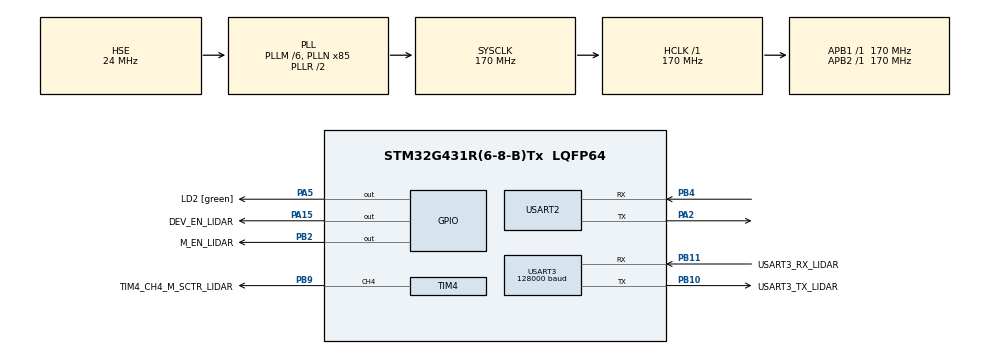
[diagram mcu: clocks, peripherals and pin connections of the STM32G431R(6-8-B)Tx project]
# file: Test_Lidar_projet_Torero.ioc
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Dma.Request0=USART3_TX
Dma.USART3_TX.0.Direction=DMA_MEMORY_TO_PERIPH
Dma.USART3_TX.0.EventEnable=DISABLE
Dma.USART3_TX.0.Instance=DMA1_Channel1
Dma.USART3_TX.0.MemDataAlignment=DMA_MDATAALIGN_BYTE
Dma.USART3_TX.0.MemInc=DMA_MINC_ENABLE
Dma.USART3_TX.0.Mode=DMA_CIRCULAR
Dma.USART3_TX.0.PeriphDataAlignment=DMA_PDATAALIGN_BYTE
Dma.USART3_TX.0.PeriphInc=DMA_PINC_DISABLE
Dma.USART3_TX.0.Polarity=HAL_DMAMUX_REQ_GEN_RISING
Dma.USART3_TX.0.Priority=DMA_PRIORITY_LOW
Dma.USART3_TX.0.RequestNumber=1
Dma.USART3_TX.0.SignalID=NONE
Dma.USART3_TX.0.SyncEnable=DISABLE
Dma.USART3_TX.0.SyncPolarity=HAL_DMAMUX_SYNC_NO_EVENT
Dma.USART3_TX.0.SyncRequestNumber=1
Dma.USART3_TX.0.SyncSignalID=NONE
Mcu.Family=STM32G4
Mcu.Name=STM32G431R(6-8-B)Tx
Mcu.Package=LQFP64
NVIC.DMA1_Channel1_IRQn=true\:0\:0\:false\:false\:true\:false\:true\:true
NVIC.PriorityGroup=NVIC_PRIORITYGROUP_4
PA13.GPIO_Label=T_SWDIO
PA13.Mode=Serial_Wire
PA13.Signal=SYS_JTMS-SWDIO
PA14.GPIO_Label=T_SWCLK
PA14.Mode=Serial_Wire
PA14.Signal=SYS_JTCK-SWCLK
PA15.GPIO_Label=DEV_EN_LIDAR
PA15.Signal=GPIO_Output
PA2.Mode=Asynchronous
PA2.Signal=USART2_TX
PA5.GPIO_Label=LD2 [green]
PA5.Signal=GPIO_Output
PB10.GPIO_Label=USART3_TX_LIDAR
PB10.Mode=Asynchronous
PB10.Signal=USART3_TX
PB11.GPIO_Label=USART3_RX_LIDAR
PB11.Mode=Asynchronous
PB11.Signal=USART3_RX
PB2.GPIO_Label=M_EN_LIDAR
PB2.PinState=GPIO_PIN_SET
PB2.Signal=GPIO_Output
PB3.GPIO_Label=T_SWO
PB3.Signal=SYS_JTDO-SWO
PB4.Mode=Asynchronous
PB4.Signal=USART2_RX
PB9.GPIO_Label=TIM4_CH4_M_SCTR_LIDAR
PB9.Signal=S_TIM4_CH4
PC14-OSC32_IN.GPIO_Label=RCC_OSC32_OUT
PC14-OSC32_IN.Signal=RCC_OSC32_IN
PC15-OSC32_OUT.GPIO_Label=RCC_OSC32_OUT
PC15-OSC32_OUT.Signal=RCC_OSC32_OUT
PF0-OSC_IN.GPIO_Label=RCC_OSC_IN
PF0-OSC_IN.Mode=HSE-External-Oscillator
PF0-OSC_IN.Signal=RCC_OSC_IN
PF1-OSC_OUT.GPIO_Label=RCC_OSC_OUT
PF1-OSC_OUT.Mode=HSE-External-Oscillator
PF1-OSC_OUT.Signal=RCC_OSC_OUT
ProjectManager.HeapSize=0x200
ProjectManager.StackSize=0x400
ProjectManager.TargetToolchain=STM32CubeIDE
RCC.ADC12Freq_Value=170000000
RCC.AHBFreq_Value=170000000
RCC.APB1Freq_Value=170000000
RCC.APB1TimFreq_Value=170000000
RCC.APB2Freq_Value=170000000
RCC.APB2TimFreq_Value=170000000
RCC.CortexFreq_Value=170000000
RCC.EXTERNAL_CLOCK_VALUE=12288000
RCC.HCLKFreq_Value=170000000
RCC.HSE_VALUE=24000000
RCC.HSI48_VALUE=48000000
RCC.HSI_VALUE=16000000
RCC.LSE_VALUE=32768
RCC.PLLM=RCC_PLLM_DIV6
RCC.PLLN=85
RCC.PLLSourceVirtual=RCC_PLLSOURCE_HSE
RCC.RTCClockSelection=RCC_RTCCLKSOURCE_LSE
RCC.SYSCLKFreq_VALUE=170000000
RCC.SYSCLKSource=RCC_SYSCLKSOURCE_PLLCLK
RCC.USBFreq_Value=170000000
RCC.VCOOutputFreq_Value=340000000
SH.S_TIM4_CH4.0=TIM4_CH4,PWM Generation4 CH4
TIM4.Channel-PWM\ Generation4\ CH4=TIM_CHANNEL_4
USART2.VirtualMode-Asynchronous=VM_ASYNC
USART3.BaudRate=128000
USART3.VirtualMode-Asynchronous=VM_ASYNC
USART3.WordLength=WORDLENGTH_8B
VP_SYS_VS_DBSignals.Mode=DisableDeadBatterySignals
VP_TIM4_VS_ClockSourceINT.Mode=Internal
board=NUCLEO-G431RB

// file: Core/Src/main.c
/* USER CODE BEGIN Header */
/**
  ******************************************************************************
  * @file           : main.c
  * @brief          : Main program body
  ******************************************************************************
  * @attention
  *
  * Copyright (c) 2024 STMicroelectronics.
  * All rights reserved.
  *
  * This software is licensed under terms that can be found in the LICENSE file
  * in the root directory of this software component.
  * If no LICENSE file comes with this software, it is provided AS-IS.
  *
  ******************************************************************************
  */
/* USER CODE END Header */
#include "main.h"

/* USER CODE BEGIN Includes */
#include "ydlidarx4_header.h"
/* USER CODE END Includes */

TIM_HandleTypeDef htim4;

UART_HandleTypeDef huart2;
UART_HandleTypeDef huart3;
DMA_HandleTypeDef hdma_usart3_tx;

/* USER CODE BEGIN PV */
LIDAR_HandleTypeDef_t hlidar;
/* USER CODE END PV */

void SystemClock_Config(void);
static void MX_GPIO_Init(void);
static void MX_DMA_Init(void);
static void MX_TIM4_Init(void);
static void MX_USART3_UART_Init(void);
static void MX_USART2_UART_Init(void);

/* USER CODE BEGIN 0 */

int __io_putchar(int chr){
	HAL_UART_Transmit(&huart2, (uint8_t*)&chr, 1, HAL_MAX_DELAY);
	return chr;
}

void print_buffer(const char * Name, uint8_t *pData, uint16_t Size, int N_lines){
	printf("%s\r\n", Name);
	if(N_lines >= (int) Size){
		for(int i = 0; i<Size; i++){
			printf("%d : %d\r\n", i, pData[i]);
		}
	}
	else{
		for(int i = 0; i<N_lines; i++){
			printf("%d : %d\r\n", i, pData[i]);
		}
	}
}
/* USER CODE END 0 */

int main(void)
{

  /* MCU Configuration--------------------------------------------------------*/

  /* Reset of all peripherals, Initializes the Flash interface and the Systick. */
  HAL_Init();

  /* Configure the system clock */
  SystemClock_Config();

  /* Initialize all configured peripherals */
  MX_GPIO_Init();
  MX_DMA_Init();
  MX_TIM4_Init();
  MX_USART3_UART_Init();
  MX_USART2_UART_Init();
  /* USER CODE BEGIN 2 */

  LIDAR_Init(&hlidar);
    HAL_Delay(500);
    LIDAR_Stop(&hlidar);
    HAL_Delay(500);
    LIDAR_Get_Health_Status(&hlidar);
    print_buffer("Health", hlidar.health_buff, HEALTH_BUFF_SIZE_LIDAR, HEALTH_BUFF_SIZE_LIDAR);
    HAL_Delay(500);
    LIDAR_Get_Info(&hlidar);
    print_buffer("Info", hlidar.info_buff, INFO_BUFF_SIZE_LIDAR, INFO_BUFF_SIZE_LIDAR);
    LIDAR_Start(&hlidar);

  /* USER CODE END 2 */

  /* Infinite loop */
  /* USER CODE BEGIN WHILE */
  while (1)
  {
	  LIDAR_get_point(&hlidar);
	  LIDAR_process_frame(&hlidar);
	  print_buffer("POINT", hlidar.process_frame.point_buff, POINT_BUFF_SIZE_LIDAR, 50);
	  LIDAR_median_filter(&hlidar);
	  print_buffer("FILTERED", hlidar.process_frame.filtered_buff, POINT_BUFF_SIZE_LIDAR, 50);
	  HAL_Delay(1);
    /* USER CODE END WHILE */

  }
}

void SystemClock_Config(void)
{
  RCC_OscInitTypeDef RCC_OscInitStruct = {0};
  RCC_ClkInitTypeDef RCC_ClkInitStruct = {0};

  /** Configure the main internal regulator output voltage
  */
  HAL_PWREx_ControlVoltageScaling(PWR_REGULATOR_VOLTAGE_SCALE1_BOOST);

  /** Initializes the RCC Oscillators according to the specified parameters
  * in the RCC_OscInitTypeDef structure.
  */
  RCC_OscInitStruct.OscillatorType = RCC_OSCILLATORTYPE_HSE;
  RCC_OscInitStruct.HSEState = RCC_HSE_ON;
  RCC_OscInitStruct.PLL.PLLState = RCC_PLL_ON;
  RCC_OscInitStruct.PLL.PLLSource = RCC_PLLSOURCE_HSE;
  RCC_OscInitStruct.PLL.PLLM = RCC_PLLM_DIV6;
  RCC_OscInitStruct.PLL.PLLN = 85;
  RCC_OscInitStruct.PLL.PLLP = RCC_PLLP_DIV2;
  RCC_OscInitStruct.PLL.PLLQ = RCC_PLLQ_DIV2;
  RCC_OscInitStruct.PLL.PLLR = RCC_PLLR_DIV2;
  if (HAL_RCC_OscConfig(&RCC_OscInitStruct) != HAL_OK)
  {
    Error_Handler();
  }

  /** Initializes the CPU, AHB and APB buses clocks
  */
  RCC_ClkInitStruct.ClockType = RCC_CLOCKTYPE_HCLK|RCC_CLOCKTYPE_SYSCLK
                              |RCC_CLOCKTYPE_PCLK1|RCC_CLOCKTYPE_PCLK2;
  RCC_ClkInitStruct.SYSCLKSource = RCC_SYSCLKSOURCE_PLLCLK;
  RCC_ClkInitStruct.AHBCLKDivider = RCC_SYSCLK_DIV1;
  RCC_ClkInitStruct.APB1CLKDivider = RCC_HCLK_DIV1;
  RCC_ClkInitStruct.APB2CLKDivider = RCC_HCLK_DIV1;

  if (HAL_RCC_ClockConfig(&RCC_ClkInitStruct, FLASH_LATENCY_4) != HAL_OK)
  {
    Error_Handler();
  }
}

static void MX_TIM4_Init(void)
{

  TIM_ClockConfigTypeDef sClockSourceConfig = {0};
  TIM_MasterConfigTypeDef sMasterConfig = {0};
  TIM_OC_InitTypeDef sConfigOC = {0};

  htim4.Instance = TIM4;
  htim4.Init.Prescaler = 0;
  htim4.Init.CounterMode = TIM_COUNTERMODE_UP;
  htim4.Init.Period = 65535;
  htim4.Init.ClockDivision = TIM_CLOCKDIVISION_DIV1;
  htim4.Init.AutoReloadPreload = TIM_AUTORELOAD_PRELOAD_DISABLE;
  if (HAL_TIM_Base_Init(&htim4) != HAL_OK)
  {
    Error_Handler();
  }
  sClockSourceConfig.ClockSource = TIM_CLOCKSOURCE_INTERNAL;
  if (HAL_TIM_ConfigClockSource(&htim4, &sClockSourceConfig) != HAL_OK)
  {
    Error_Handler();
  }
  if (HAL_TIM_PWM_Init(&htim4) != HAL_OK)
  {
    Error_Handler();
  }
  sMasterConfig.MasterOutputTrigger = TIM_TRGO_RESET;
  sMasterConfig.MasterSlaveMode = TIM_MASTERSLAVEMODE_DISABLE;
  if (HAL_TIMEx_MasterConfigSynchronization(&htim4, &sMasterConfig) != HAL_OK)
  {
    Error_Handler();
  }
  sConfigOC.OCMode = TIM_OCMODE_PWM1;
  sConfigOC.Pulse = 0;
  sConfigOC.OCPolarity = TIM_OCPOLARITY_HIGH;
  sConfigOC.OCFastMode = TIM_OCFAST_DISABLE;
  if (HAL_TIM_PWM_ConfigChannel(&htim4, &sConfigOC, TIM_CHANNEL_4) != HAL_OK)
  {
    Error_Handler();
  }
  HAL_TIM_MspPostInit(&htim4);

}

static void MX_USART2_UART_Init(void)
{

  huart2.Instance = USART2;
  huart2.Init.BaudRate = 115200;
  huart2.Init.WordLength = UART_WORDLENGTH_8B;
  huart2.Init.StopBits = UART_STOPBITS_1;
  huart2.Init.Parity = UART_PARITY_NONE;
  huart2.Init.Mode = UART_MODE_TX_RX;
  huart2.Init.HwFlowCtl = UART_HWCONTROL_NONE;
  huart2.Init.OverSampling = UART_OVERSAMPLING_16;
  huart2.Init.OneBitSampling = UART_ONE_BIT_SAMPLE_DISABLE;
  huart2.Init.ClockPrescaler = UART_PRESCALER_DIV1;
  huart2.AdvancedInit.AdvFeatureInit = UART_ADVFEATURE_NO_INIT;
  if (HAL_UART_Init(&huart2) != HAL_OK)
  {
    Error_Handler();
  }
  if (HAL_UARTEx_SetTxFifoThreshold(&huart2, UART_TXFIFO_THRESHOLD_1_8) != HAL_OK)
  {
    Error_Handler();
  }
  if (HAL_UARTEx_SetRxFifoThreshold(&huart2, UART_RXFIFO_THRESHOLD_1_8) != HAL_OK)
  {
    Error_Handler();
  }
  if (HAL_UARTEx_DisableFifoMode(&huart2) != HAL_OK)
  {
    Error_Handler();
  }

}

static void MX_USART3_UART_Init(void)
{

  huart3.Instance = USART3;
  huart3.Init.BaudRate = 128000;
  huart3.Init.WordLength = UART_WORDLENGTH_8B;
  huart3.Init.StopBits = UART_STOPBITS_1;
  huart3.Init.Parity = UART_PARITY_NONE;
  huart3.Init.Mode = UART_MODE_TX_RX;
  huart3.Init.HwFlowCtl = UART_HWCONTROL_NONE;
  huart3.Init.OverSampling = UART_OVERSAMPLING_16;
  huart3.Init.OneBitSampling = UART_ONE_BIT_SAMPLE_DISABLE;
  huart3.Init.ClockPrescaler = UART_PRESCALER_DIV1;
  huart3.AdvancedInit.AdvFeatureInit = UART_ADVFEATURE_NO_INIT;
  if (HAL_UART_Init(&huart3) != HAL_OK)
  {
    Error_Handler();
  }
  if (HAL_UARTEx_SetTxFifoThreshold(&huart3, UART_TXFIFO_THRESHOLD_1_8) != HAL_OK)
  {
    Error_Handler();
  }
  if (HAL_UARTEx_SetRxFifoThreshold(&huart3, UART_RXFIFO_THRESHOLD_1_8) != HAL_OK)
  {
    Error_Handler();
  }
  if (HAL_UARTEx_DisableFifoMode(&huart3) != HAL_OK)
  {
    Error_Handler();
  }

}

static void MX_DMA_Init(void)
{

  /* DMA controller clock enable */
  __HAL_RCC_DMAMUX1_CLK_ENABLE();
  __HAL_RCC_DMA1_CLK_ENABLE();

  /* DMA interrupt init */
  /* DMA1_Channel1_IRQn interrupt configuration */
  HAL_NVIC_SetPriority(DMA1_Channel1_IRQn, 0, 0);
  HAL_NVIC_EnableIRQ(DMA1_Channel1_IRQn);

}

static void MX_GPIO_Init(void)
{
  GPIO_InitTypeDef GPIO_InitStruct = {0};

  /* GPIO Ports Clock Enable */
  __HAL_RCC_GPIOC_CLK_ENABLE();
  __HAL_RCC_GPIOF_CLK_ENABLE();
  __HAL_RCC_GPIOA_CLK_ENABLE();
  __HAL_RCC_GPIOB_CLK_ENABLE();

  /*Configure GPIO pin Output Level */
  HAL_GPIO_WritePin(GPIOA, LD2_Pin|DEV_EN_LIDAR_Pin, GPIO_PIN_RESET);

  /*Configure GPIO pin Output Level */
  HAL_GPIO_WritePin(M_EN_LIDAR_GPIO_Port, M_EN_LIDAR_Pin, GPIO_PIN_SET);

  /*Configure GPIO pin : B1_Pin */
  GPIO_InitStruct.Pin = B1_Pin;
  GPIO_InitStruct.Mode = GPIO_MODE_IT_RISING;
  GPIO_InitStruct.Pull = GPIO_NOPULL;
  HAL_GPIO_Init(B1_GPIO_Port, &GPIO_InitStruct);

  /*Configure GPIO pin : LPUART1_RX_Pin */
  GPIO_InitStruct.Pin = LPUART1_RX_Pin;
  GPIO_InitStruct.Mode = GPIO_MODE_AF_PP;
  GPIO_InitStruct.Pull = GPIO_NOPULL;
  GPIO_InitStruct.Speed = GPIO_SPEED_FREQ_LOW;
  GPIO_InitStruct.Alternate = GPIO_AF12_LPUART1;
  HAL_GPIO_Init(LPUART1_RX_GPIO_Port, &GPIO_InitStruct);

  /*Configure GPIO pins : LD2_Pin DEV_EN_LIDAR_Pin */
  GPIO_InitStruct.Pin = LD2_Pin|DEV_EN_LIDAR_Pin;
  GPIO_InitStruct.Mode = GPIO_MODE_OUTPUT_PP;
  GPIO_InitStruct.Pull = GPIO_NOPULL;
  GPIO_InitStruct.Speed = GPIO_SPEED_FREQ_LOW;
  HAL_GPIO_Init(GPIOA, &GPIO_InitStruct);

  /*Configure GPIO pin : M_EN_LIDAR_Pin */
  GPIO_InitStruct.Pin = M_EN_LIDAR_Pin;
  GPIO_InitStruct.Mode = GPIO_MODE_OUTPUT_PP;
  GPIO_InitStruct.Pull = GPIO_NOPULL;
  GPIO_InitStruct.Speed = GPIO_SPEED_FREQ_LOW;
  HAL_GPIO_Init(M_EN_LIDAR_GPIO_Port, &GPIO_InitStruct);

}

void Error_Handler(void)
{
  __disable_irq();
  while (1)
  {
  }
}
